VERSION 5.7 ;
  NOWIREEXTENSIONATPIN ON ;
  DIVIDERCHAR "/" ;
  BUSBITCHARS "[]" ;
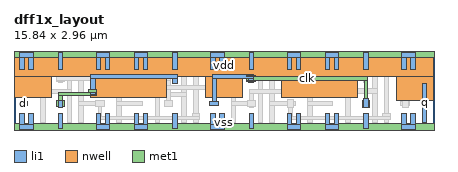
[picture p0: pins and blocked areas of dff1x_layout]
MACRO dff1x_layout
  CLASS BLOCK ;
  FOREIGN dff1x_layout ;
  ORIGIN 2.480 3.430 ;
  SIZE 15.840 BY 2.960 ;
  PIN q
    ANTENNADIFFAREA 0.531000 ;
    PORT
      LAYER li1 ;
        RECT 12.920 -3.130 13.090 -1.680 ;
    END
  END q
  PIN vdd
    ANTENNADIFFAREA 5.850000 ;
    PORT
      LAYER nwell ;
        RECT -2.470 -1.430 13.340 -0.590 ;
        RECT -2.470 -2.210 -1.060 -1.430 ;
        RECT 0.410 -2.210 3.260 -1.430 ;
        RECT 4.730 -2.210 6.140 -1.430 ;
        RECT 7.610 -2.210 10.460 -1.430 ;
        RECT 11.930 -2.300 13.340 -1.430 ;
      LAYER li1 ;
        RECT -2.260 -0.680 -1.750 -0.510 ;
        RECT -2.260 -1.160 -2.090 -0.680 ;
        RECT -1.920 -1.160 -1.750 -0.680 ;
        RECT -0.810 -1.150 -0.640 -0.510 ;
        RECT 0.620 -0.680 1.130 -0.510 ;
        RECT 0.620 -1.160 0.790 -0.680 ;
        RECT 0.960 -1.160 1.130 -0.680 ;
        RECT 2.060 -0.680 2.570 -0.510 ;
        RECT 2.060 -1.160 2.230 -0.680 ;
        RECT 2.400 -1.160 2.570 -0.680 ;
        RECT 3.510 -1.150 3.680 -0.510 ;
        RECT 4.940 -0.680 5.450 -0.510 ;
        RECT 4.940 -1.160 5.110 -0.680 ;
        RECT 5.280 -1.160 5.450 -0.680 ;
        RECT 6.390 -1.150 6.560 -0.510 ;
        RECT 7.820 -0.680 8.330 -0.510 ;
        RECT 7.820 -1.160 7.990 -0.680 ;
        RECT 8.160 -1.160 8.330 -0.680 ;
        RECT 9.260 -0.680 9.770 -0.510 ;
        RECT 9.260 -1.160 9.430 -0.680 ;
        RECT 9.600 -1.160 9.770 -0.680 ;
        RECT 10.710 -1.150 10.880 -0.510 ;
        RECT 12.140 -0.680 12.650 -0.510 ;
        RECT 12.140 -1.160 12.310 -0.680 ;
        RECT 12.480 -1.160 12.650 -0.680 ;
      LAYER met1 ;
        RECT -2.480 -0.710 13.360 -0.470 ;
    END
  END vdd
  PIN vss
    ANTENNADIFFAREA 2.268000 ;
    PORT
      LAYER li1 ;
        RECT -2.260 -3.230 -2.090 -2.810 ;
        RECT -1.920 -3.230 -1.750 -2.810 ;
        RECT -2.260 -3.400 -1.750 -3.230 ;
        RECT -0.810 -3.390 -0.640 -2.810 ;
        RECT 0.620 -3.230 0.790 -2.810 ;
        RECT 0.960 -3.230 1.130 -2.810 ;
        RECT 0.620 -3.400 1.130 -3.230 ;
        RECT 2.060 -3.230 2.230 -2.810 ;
        RECT 2.400 -3.230 2.570 -2.810 ;
        RECT 2.060 -3.400 2.570 -3.230 ;
        RECT 3.510 -3.390 3.680 -2.810 ;
        RECT 4.940 -3.230 5.110 -2.810 ;
        RECT 5.280 -3.230 5.450 -2.810 ;
        RECT 4.940 -3.400 5.450 -3.230 ;
        RECT 6.390 -3.390 6.560 -2.810 ;
        RECT 7.820 -3.230 7.990 -2.810 ;
        RECT 8.160 -3.230 8.330 -2.810 ;
        RECT 7.820 -3.400 8.330 -3.230 ;
        RECT 9.260 -3.230 9.430 -2.810 ;
        RECT 9.600 -3.230 9.770 -2.810 ;
        RECT 9.260 -3.400 9.770 -3.230 ;
        RECT 10.710 -3.390 10.880 -2.810 ;
        RECT 12.140 -3.230 12.310 -2.810 ;
        RECT 12.480 -3.230 12.650 -2.810 ;
        RECT 12.140 -3.400 12.650 -3.230 ;
      LAYER met1 ;
        RECT -2.480 -3.430 13.360 -3.190 ;
    END
  END vss
  PIN d
    ANTENNAGATEAREA 0.252000 ;
    PORT
      LAYER li1 ;
        RECT -2.290 -2.520 -1.960 -2.350 ;
    END
  END d
  PIN clk
    ANTENNAGATEAREA 0.504000 ;
    PORT
      LAYER li1 ;
        RECT 6.380 -1.330 6.550 -1.320 ;
        RECT 0.410 -1.500 3.670 -1.330 ;
        RECT 0.410 -2.100 0.580 -1.500 ;
        RECT 3.500 -1.660 3.670 -1.500 ;
        RECT 4.990 -1.500 6.550 -1.330 ;
        RECT -0.810 -2.590 -0.640 -2.260 ;
        RECT 4.990 -2.350 5.160 -1.500 ;
        RECT 6.380 -1.650 6.550 -1.500 ;
        RECT 4.910 -2.520 5.240 -2.350 ;
        RECT 10.710 -2.590 10.880 -2.260 ;
      LAYER met1 ;
        RECT 6.300 -1.410 6.630 -1.370 ;
        RECT 6.300 -1.550 10.860 -1.410 ;
        RECT 6.300 -1.610 6.630 -1.550 ;
        RECT 0.340 -2.000 0.640 -1.890 ;
        RECT -0.790 -2.140 0.640 -2.000 ;
        RECT -0.790 -2.300 -0.650 -2.140 ;
        RECT 10.720 -2.300 10.860 -1.550 ;
        RECT -0.890 -2.550 -0.560 -2.300 ;
        RECT 10.650 -2.570 10.940 -2.300 ;
    END
  END clk
  OBS
      LAYER li1 ;
        RECT -0.820 -1.650 -0.650 -1.320 ;
        RECT -1.480 -1.900 -1.310 -1.680 ;
        RECT -0.470 -1.900 -0.300 -0.820 ;
        RECT -1.480 -2.070 -0.300 -1.900 ;
        RECT -1.480 -3.130 -1.310 -2.070 ;
        RECT -0.470 -3.140 -0.300 -2.070 ;
        RECT -0.030 -2.350 0.140 -0.810 ;
        RECT 1.420 -1.160 1.590 -0.830 ;
        RECT 1.400 -2.350 1.570 -1.680 ;
        RECT 2.840 -2.010 3.010 -1.680 ;
        RECT 3.850 -2.010 4.020 -0.820 ;
        RECT 2.840 -2.180 4.020 -2.010 ;
        RECT -0.030 -2.520 0.920 -2.350 ;
        RECT 1.400 -2.520 2.360 -2.350 ;
        RECT -0.030 -3.130 0.140 -2.520 ;
        RECT 1.400 -3.130 1.570 -2.520 ;
        RECT 2.840 -3.130 3.010 -2.180 ;
        RECT 3.180 -2.520 3.510 -2.350 ;
        RECT 3.850 -3.140 4.020 -2.180 ;
        RECT 4.290 -3.130 4.460 -0.810 ;
        RECT 5.720 -2.340 5.890 -1.680 ;
        RECT 6.390 -2.340 6.560 -2.260 ;
        RECT 5.720 -2.510 6.560 -2.340 ;
        RECT 5.720 -3.130 5.890 -2.510 ;
        RECT 6.390 -2.590 6.560 -2.510 ;
        RECT 6.730 -3.140 6.900 -0.820 ;
        RECT 7.170 -2.350 7.340 -0.810 ;
        RECT 8.620 -1.160 8.790 -0.830 ;
        RECT 10.700 -1.330 10.870 -1.320 ;
        RECT 9.350 -1.500 10.870 -1.330 ;
        RECT 8.600 -2.350 8.770 -1.680 ;
        RECT 9.350 -2.080 9.520 -1.500 ;
        RECT 10.700 -1.650 10.870 -1.500 ;
        RECT 10.040 -1.880 10.210 -1.680 ;
        RECT 11.050 -1.880 11.220 -0.820 ;
        RECT 10.040 -2.050 11.220 -1.880 ;
        RECT 7.170 -2.520 8.120 -2.350 ;
        RECT 8.600 -2.520 9.550 -2.350 ;
        RECT 7.170 -3.130 7.340 -2.520 ;
        RECT 8.600 -3.130 8.770 -2.520 ;
        RECT 10.040 -3.130 10.210 -2.050 ;
        RECT 11.050 -3.140 11.220 -2.050 ;
        RECT 11.490 -3.130 11.660 -0.810 ;
        RECT 12.110 -2.520 12.440 -2.350 ;
      LAYER met1 ;
        RECT 1.360 -0.940 1.650 -0.880 ;
        RECT 6.660 -0.940 6.960 -0.880 ;
        RECT 1.360 -1.080 6.960 -0.940 ;
        RECT 1.360 -1.130 1.650 -1.080 ;
        RECT 6.660 -1.130 6.960 -1.080 ;
        RECT 8.560 -0.940 8.850 -0.880 ;
        RECT 8.560 -1.080 12.340 -0.940 ;
        RECT 8.560 -1.130 8.850 -1.080 ;
        RECT -0.880 -1.410 -0.590 -1.360 ;
        RECT -0.880 -1.550 3.420 -1.410 ;
        RECT -0.880 -1.600 -0.590 -1.550 ;
        RECT 3.280 -1.750 3.420 -1.550 ;
        RECT 5.660 -1.750 5.960 -1.680 ;
        RECT 3.280 -1.890 5.960 -1.750 ;
        RECT 3.280 -2.310 3.420 -1.890 ;
        RECT 5.660 -1.960 5.960 -1.890 ;
        RECT 9.290 -1.920 9.580 -1.850 ;
        RECT 6.400 -2.060 9.580 -1.920 ;
        RECT 6.400 -2.310 6.540 -2.060 ;
        RECT 9.290 -2.140 9.580 -2.060 ;
        RECT 12.200 -2.290 12.340 -1.080 ;
        RECT 0.600 -2.550 0.920 -2.310 ;
        RECT 0.690 -2.910 0.830 -2.550 ;
        RECT 3.180 -2.560 3.490 -2.310 ;
        RECT 6.310 -2.550 6.640 -2.310 ;
        RECT 7.840 -2.580 8.070 -2.290 ;
        RECT 12.160 -2.580 12.400 -2.290 ;
        RECT 4.250 -2.910 4.520 -2.790 ;
        RECT 0.690 -3.050 4.520 -2.910 ;
        RECT 7.890 -2.910 8.030 -2.580 ;
        RECT 11.430 -2.910 11.720 -2.800 ;
        RECT 7.890 -3.050 11.720 -2.910 ;
  END
END dff1x_layout
END LIBRARY

